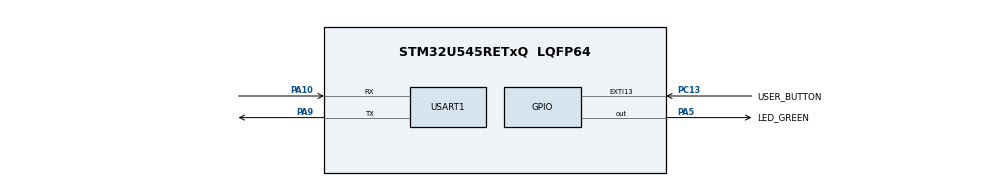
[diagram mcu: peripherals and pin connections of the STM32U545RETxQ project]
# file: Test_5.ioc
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CORTEX_M33_NS.userName=CORTEX_M33
Mcu.Family=STM32U5
Mcu.Name=STM32U545RETxQ
Mcu.Package=LQFP64
NVIC.EXTI13_IRQn=true\:0\:0\:false\:false\:true\:true\:true\:true
NVIC.PriorityGroup=NVIC_PRIORITYGROUP_4
NVIC.USART1_IRQn=true\:0\:0\:false\:false\:true\:true\:true\:true
PA10.Mode=Asynchronous
PA10.Signal=USART1_RX
PA5.GPIO_Label=LED_GREEN
PA5.GPIO_PuPd=GPIO_PULLUP
PA5.GPIO_Speed=GPIO_SPEED_FREQ_HIGH
PA5.Signal=GPIO_Output
PA9.Mode=Asynchronous
PA9.Signal=USART1_TX
PC13.GPIO_Label=USER_BUTTON
PC13.GPIO_ModeDefaultEXTI=GPIO_MODE_IT_FALLING
PC13.GPIO_PuPd=GPIO_PULLDOWN
PC13.Signal=GPXTI13
PWR.PowerMode=PWR_SMPS_SUPPLY
ProjectManager.HeapSize=0x200
ProjectManager.StackSize=0x400
ProjectManager.TargetToolchain=STM32CubeIDE
RCC.ADCFreq_Value=16000000
RCC.AHBFreq_Value=12000000
RCC.APB1Freq_Value=12000000
RCC.APB1TimFreq_Value=12000000
RCC.APB2Freq_Value=12000000
RCC.APB2TimFreq_Value=12000000
RCC.APB3Freq_Value=12000000
RCC.CortexFreq_Value=12000000
RCC.DACCLockSelectionVirtual=RCC_DAC1CLKSOURCE_LSI
RCC.DACCLockSelectionVirtualString=RCC_DAC1CLKSOURCE_LSI
RCC.EPOD_VALUE=16000000
RCC.HCLKFreq_Value=12000000
RCC.HSE_VALUE=16000000
RCC.HSI48_VALUE=48000000
RCC.HSI_VALUE=16000000
RCC.LSE_VALUE=32768
RCC.LSIDIV_VALUE=32000
RCC.MSIClockRange=RCC_MSIRANGE_3
RCC.MSI_VALUE=12000000
RCC.PLLSourceVirtual=RCC_PLLSOURCE_HSI
RCC.SYSCLKFreq_VALUE=12000000
RCC.USBFreq_Value=48000000
RCC.VCOOutputFreq_Value=2064000000
USART1.VirtualMode-Asynchronous=VM_ASYNC
VP_ICACHE_VS_ICACHE.Mode=DirectMappedCache
VP_LPBAMQUEUE_VS_QUEUE.Mode=QUEUEMODE
VP_LPBAM_VS_SIG1.Mode=SmartRun
VP_LPBAM_VS_SIG4.Mode=LPDMA1
VP_MEMORYMAP_VS_MEMORYMAP.Mode=CurAppReg
VP_NUCLEO-U545RE-Q_VS_BSP_COMMON.Mode=COMMON
VP_PWR_VS_LPOM.Mode=PowerOptimisation
VP_PWR_VS_SECSignals.Mode=Security/Privilege
board=NUCLEO-U545RE-Q

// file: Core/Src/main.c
/* USER CODE BEGIN Header */
/**
 ******************************************************************************
 * @file           : main.c
 * @brief          : Main program body
 ******************************************************************************
 * @attention
 *
 * Copyright (c) 2025 STMicroelectronics.
 * All rights reserved.
 *
 * This software is licensed under terms that can be found in the LICENSE file
 * in the root directory of this software component.
 * If no LICENSE file comes with this software, it is provided AS-IS.
 *
 ******************************************************************************
 */
/* USER CODE END Header */
#include "main.h"

/* USER CODE BEGIN Includes */
#include <string.h>
#include <stdio.h>
#define RX_BUFFER_SIZE 32
/* USER CODE END Includes */

UART_HandleTypeDef huart1;

/* USER CODE BEGIN PV */
uint8_t received_char;
uint8_t rx_buffer[RX_BUFFER_SIZE];
uint8_t rx_index = 0;
volatile uint8_t data_ready_flag = 0;

/* USER CODE END PV */

void SystemClock_Config(void);
static void SystemPower_Config(void);
static void MX_GPIO_Init(void);
static void MX_ICACHE_Init(void);
static void MX_USART1_UART_Init(void);

int main(void)
{

  /* MCU Configuration--------------------------------------------------------*/

  /* Reset of all peripherals, Initializes the Flash interface and the Systick. */
  HAL_Init();

  /* Configure the System Power */
  SystemPower_Config();

  /* Configure the system clock */
  SystemClock_Config();

  /* Initialize all configured peripherals */
  MX_GPIO_Init();
  MX_ICACHE_Init();
  MX_USART1_UART_Init();
  /* USER CODE BEGIN 2 */
	HAL_UART_Receive_IT(&huart1, &received_char, 1);

  /* USER CODE END 2 */

  /* Infinite loop */
  /* USER CODE BEGIN WHILE */
	while (1) {
		if (data_ready_flag == 1) {
			// Reset the flag
			data_ready_flag = 0;

			// Buffer for the response string
			char tx_buffer[50];

			// Compare the received string and prepare the response
			HAL_GPIO_TogglePin(GPIOA, GPIO_PIN_5);

			//sprintf(tx_buffer, (char*) rx_buffer);

			// Transmit the response
			HAL_UART_Transmit(&huart1, (uint8_t*) tx_buffer, strlen(tx_buffer), HAL_MAX_DELAY);
		}

    /* USER CODE END WHILE */

	}
}

void SystemClock_Config(void)
{
  RCC_OscInitTypeDef RCC_OscInitStruct = {0};
  RCC_ClkInitTypeDef RCC_ClkInitStruct = {0};

  /** Configure the main internal regulator output voltage
  */
  if (HAL_PWREx_ControlVoltageScaling(PWR_REGULATOR_VOLTAGE_SCALE3) != HAL_OK)
  {
    Error_Handler();
  }

  /** Initializes the CPU, AHB and APB buses clocks
  */
  RCC_OscInitStruct.OscillatorType = RCC_OSCILLATORTYPE_MSI;
  RCC_OscInitStruct.MSIState = RCC_MSI_ON;
  RCC_OscInitStruct.MSICalibrationValue = RCC_MSICALIBRATION_DEFAULT;
  RCC_OscInitStruct.MSIClockRange = RCC_MSIRANGE_4;
  RCC_OscInitStruct.PLL.PLLState = RCC_PLL_ON;
  RCC_OscInitStruct.PLL.PLLSource = RCC_PLLSOURCE_MSI;
  RCC_OscInitStruct.PLL.PLLMBOOST = RCC_PLLMBOOST_DIV1;
  RCC_OscInitStruct.PLL.PLLM = 1;
  RCC_OscInitStruct.PLL.PLLN = 100;
  RCC_OscInitStruct.PLL.PLLP = 2;
  RCC_OscInitStruct.PLL.PLLQ = 2;
  RCC_OscInitStruct.PLL.PLLR = 50;
  RCC_OscInitStruct.PLL.PLLRGE = RCC_PLLVCIRANGE_0;
  RCC_OscInitStruct.PLL.PLLFRACN = 0;
  if (HAL_RCC_OscConfig(&RCC_OscInitStruct) != HAL_OK)
  {
    Error_Handler();
  }

  /** Initializes the CPU, AHB and APB buses clocks
  */
  RCC_ClkInitStruct.ClockType = RCC_CLOCKTYPE_HCLK|RCC_CLOCKTYPE_SYSCLK
                              |RCC_CLOCKTYPE_PCLK1|RCC_CLOCKTYPE_PCLK2
                              |RCC_CLOCKTYPE_PCLK3;
  RCC_ClkInitStruct.SYSCLKSource = RCC_SYSCLKSOURCE_PLLCLK;
  RCC_ClkInitStruct.AHBCLKDivider = RCC_SYSCLK_DIV1;
  RCC_ClkInitStruct.APB1CLKDivider = RCC_HCLK_DIV1;
  RCC_ClkInitStruct.APB2CLKDivider = RCC_HCLK_DIV1;
  RCC_ClkInitStruct.APB3CLKDivider = RCC_HCLK_DIV1;

  if (HAL_RCC_ClockConfig(&RCC_ClkInitStruct, FLASH_LATENCY_0) != HAL_OK)
  {
    Error_Handler();
  }
}

/**
  * @brief Power Configuration
  * @retval None
  */
static void SystemPower_Config(void)
{

  /*
   * Switch to SMPS regulator instead of LDO
   */
  if (HAL_PWREx_ConfigSupply(PWR_SMPS_SUPPLY) != HAL_OK)
  {
    Error_Handler();
  }
}

static void MX_ICACHE_Init(void)
{

  /** Enable instruction cache in 1-way (direct mapped cache)
  */
  if (HAL_ICACHE_ConfigAssociativityMode(ICACHE_1WAY) != HAL_OK)
  {
    Error_Handler();
  }
  if (HAL_ICACHE_Enable() != HAL_OK)
  {
    Error_Handler();
  }

}

static void MX_USART1_UART_Init(void)
{

  huart1.Instance = USART1;
  huart1.Init.BaudRate = 115200;
  huart1.Init.WordLength = UART_WORDLENGTH_8B;
  huart1.Init.StopBits = UART_STOPBITS_1;
  huart1.Init.Parity = UART_PARITY_NONE;
  huart1.Init.Mode = UART_MODE_TX_RX;
  huart1.Init.HwFlowCtl = UART_HWCONTROL_NONE;
  huart1.Init.OverSampling = UART_OVERSAMPLING_16;
  huart1.Init.OneBitSampling = UART_ONE_BIT_SAMPLE_DISABLE;
  huart1.Init.ClockPrescaler = UART_PRESCALER_DIV1;
  huart1.AdvancedInit.AdvFeatureInit = UART_ADVFEATURE_NO_INIT;
  if (HAL_UART_Init(&huart1) != HAL_OK)
  {
    Error_Handler();
  }
  if (HAL_UARTEx_SetTxFifoThreshold(&huart1, UART_TXFIFO_THRESHOLD_1_8) != HAL_OK)
  {
    Error_Handler();
  }
  if (HAL_UARTEx_SetRxFifoThreshold(&huart1, UART_RXFIFO_THRESHOLD_1_8) != HAL_OK)
  {
    Error_Handler();
  }
  if (HAL_UARTEx_DisableFifoMode(&huart1) != HAL_OK)
  {
    Error_Handler();
  }

}

static void MX_GPIO_Init(void)
{
  GPIO_InitTypeDef GPIO_InitStruct = {0};

  /* GPIO Ports Clock Enable */
  __HAL_RCC_GPIOC_CLK_ENABLE();
  __HAL_RCC_GPIOA_CLK_ENABLE();

  /*Configure GPIO pin Output Level */
  HAL_GPIO_WritePin(LED_GREEN_GPIO_Port, LED_GREEN_Pin, GPIO_PIN_RESET);

  /*Configure GPIO pin : USER_BUTTON_Pin */
  GPIO_InitStruct.Pin = USER_BUTTON_Pin;
  GPIO_InitStruct.Mode = GPIO_MODE_IT_FALLING;
  GPIO_InitStruct.Pull = GPIO_PULLDOWN;
  HAL_GPIO_Init(USER_BUTTON_GPIO_Port, &GPIO_InitStruct);

  /*Configure GPIO pin : LED_GREEN_Pin */
  GPIO_InitStruct.Pin = LED_GREEN_Pin;
  GPIO_InitStruct.Mode = GPIO_MODE_OUTPUT_PP;
  GPIO_InitStruct.Pull = GPIO_PULLUP;
  GPIO_InitStruct.Speed = GPIO_SPEED_FREQ_HIGH;
  HAL_GPIO_Init(LED_GREEN_GPIO_Port, &GPIO_InitStruct);

  /* EXTI interrupt init*/
  HAL_NVIC_SetPriority(EXTI13_IRQn, 0, 0);
  HAL_NVIC_EnableIRQ(EXTI13_IRQn);

}

/* USER CODE BEGIN 4 */
void HAL_UART_RxCpltCallback(UART_HandleTypeDef *huart) {
	// Check if the interrupt is from the correct UART instance
	if (huart->Instance == USART1) {
		if (received_char == '\n' || received_char == '\r')
		{
			// Null-terminate the string in the buffer
			rx_buffer[rx_index] = '\0';

			// Set the flag to indicate a complete message is ready
			data_ready_flag = 1;

			// Reset the buffer index for the next message
			rx_index = 0;
		}
		else
		{
			if (rx_index < RX_BUFFER_SIZE - 1)
			{
				rx_buffer[rx_index++] = received_char;
			}
		}
	HAL_UART_Receive_IT(&huart1, &received_char, 1);
	}
}
/* USER CODE END 4 */

void Error_Handler(void)
{
	__disable_irq();
	while (1) {
	}
}
